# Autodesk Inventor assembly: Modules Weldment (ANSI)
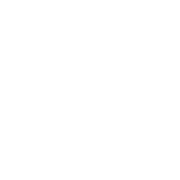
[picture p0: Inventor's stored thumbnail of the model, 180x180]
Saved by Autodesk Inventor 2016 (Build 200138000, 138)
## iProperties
Created: 2014-08
Part Number: Modules Weldment (ANSI)
Document SubType Name: Weldment
Designer: Wally
Weld Material: Welded Aluminum-6061
Author: Wally
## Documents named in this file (1)
- E:\!!AutoCAD Modules!!\!Inventor\Templates\English Templates\Modules Weldment (ANSI).iam
